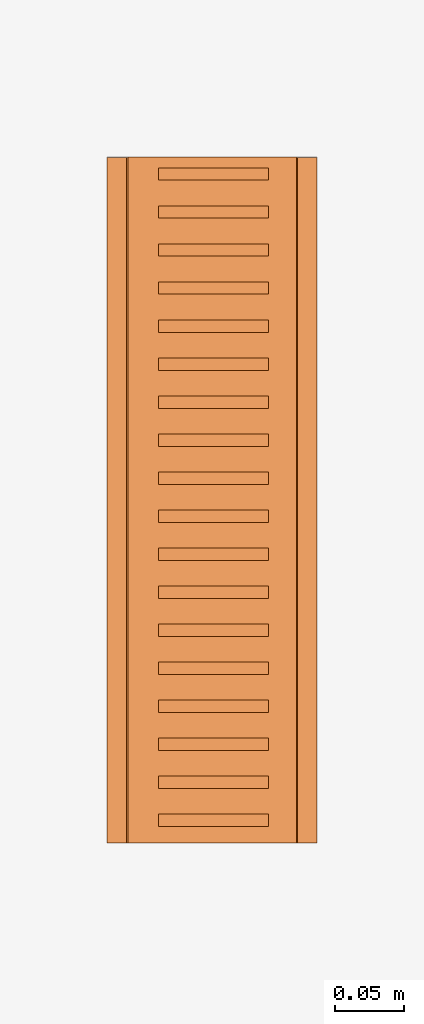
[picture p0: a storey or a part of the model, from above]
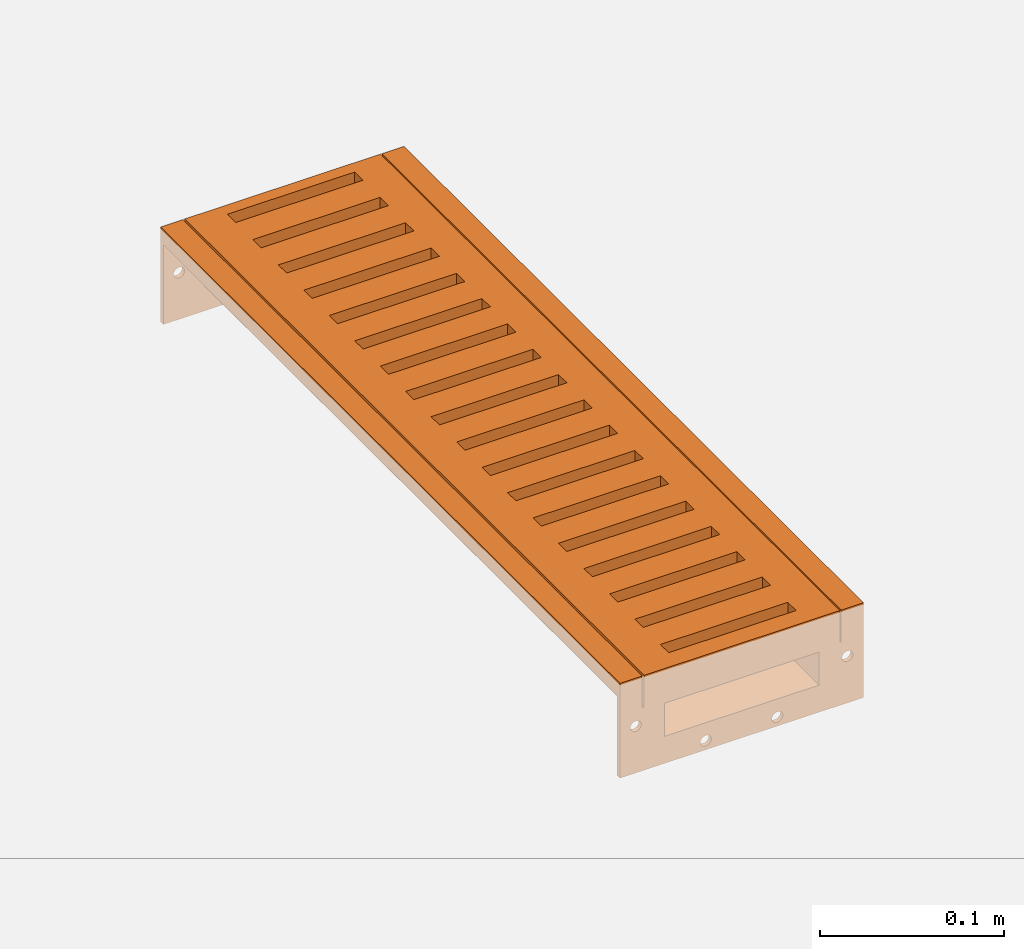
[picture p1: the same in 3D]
Properties of the parts of a building model (IFC2X3)

# File
Description: ViewDefinition [CoordinationView]
File name: 105254 - Level Invert Channel-500mm LG.ifc
Time: 2014-03-20T14:44:23
Written by: Autodesk Revit 2013
Made in: 20120221_2030(x64)

# IfcProject, Project Number
LongName: Project Name; Phase: Project Status

# IfcSite, Default
RefLatitude: 42, 21, 30, 344238; RefLongitude: -71, -3, -35, -194702; RefElevation: 0 mm

# IfcBuilding
Pset_BuildingCommon - NumberOfStoreys: 1
Other - Project Status: Project Status; Project Name: Project Name; Client Name: Owner; Project Number: Project Number; Project Address: ## Street City, State Zip; Project Issue Date: Issue Date

# IfcBuildingStorey, Level 1
LongName: Level 1; Elevation: 0 mm
Constraints - Elevation Base: 0; Elevation: 0 mm
Graphics - Line Pattern: Center; Color: 0; Line Weight: 1; Symbol: M_Level Head - Circle: M_Level Head - Circle; Symbol at End 1 Default: no; Symbol at End 2 Default: yes
Identity Data - Structural: no; Building Story: yes; Name: Level 1
Dimensions - Computation Height: 0 mm

# IfcBuildingElementProxy: 105254 - Level Invert Channel-500mm LG, ACO BD Deckline 125 Straight Channel:105254 - Level Invert Channel-500mm LG:105254 - Level Invert Channel-500mm LG:225886
In: Level 1
Material: Steel, Galvanized
Construction - 10735 - Composite Grating (White) - 500mm Long: no; 105508 - C250 Perforated Grating - 500mm Long: no; 105251 - Endplate - Invert 1: no; 105525 - C250 Slotted Grating - 1000mm Long: no; 105522 - A15 Slotted Grating - 500mm Long: no; 105524 - C250 Slotted Grating - 500mm Long: no; 105251 - Endplate - Invert 2: no; 15704 - Composite Grating (Black) - 500mm Long: no; 105509 - C250 Perforated Grating - 1000mm Long: no; 105523 - A15 Slotted Grating - 1000mm Long: no; Non Standard Channel: no; Standard Channel: yes; Grating: yes
Phasing - Phase Created: New Construction
Dimensions - Custom Channel: 494 mm; Custom Void: 2500 mm; Length: 500 mm; Void Length: -500 mm; EndCap Distance: 500 mm; Volume: 1450672 mm3; Channel Len: 494 mm
Constraints - Level: Level: Level 1; Moves With Nearby Elements: no
Pset_BuildingElementProxyCommon - Reference: 105254 - Level Invert Channel-500mm LG
Identity Data - Fax: +44 (0)1462 851490; E-mail Technical: abdtechnical@aco.co.uk; Watermark2: This file is water marked and users are prohibited to reproduce, adapt, distribute this information; Watermark1: This file is the property of ACO Technologies PLC; Telephone: +44 (0)1462 816666; Watermarked With: BIM Manager Premium Suite; Address: ACO Business Centre, Caxton Road, Bedford, MK41 0LF; Manufacturer: ACO Building Drainage; E-mail Sales: abdcommercial@aco.co.uk; Watermarked By: www.aco.co.uk; Website: www.acobd.com
General - Maintenance guidelines: X:\Electronic Literature\Building Drainage Literature\Deckline\Deckline 125.PDF; Weight (Kg): 2.3; Installation guidelines: X:\Electronic Literature\Building Drainage Literature\Deckline\Deckline 125.PDF; Dimensions (LxWxH): 500 x 153 x 63; Channel Recycled Material Content: 25 - 30 %; Seal Recyclable: Fully recyclable; Product Type: shallow invert surface water drainage system; Seal Recycled Material Content: 0%; Channel Recyclable: Fully recyclable; Load Class: A15 - C250; Seal Colour: Black; Product Range: ACO Deckline 125; Channel Material: Hot Dipped Galvanised Steel; Product Description: ACO Deckline Level Invert Channel (500 Long); Seal Material: Neoprene; Product Standard: BS EN 1433:2002 CE marked; Channel Colour: Galvanised; Product Code: 105254; Price: POA - contact ACO; NBS Specification: NBS Section Q10 Kerbs/edgings/channels/paving accessories, Clause 180 Drainage Channel Systems
Model Properties - Grating Product Code 105509: Load Class C250 - Perforated Galvanised Steel - 500mm long - 2.3kg; Grating Product Code 105522: Load Class A15 - Slotted Galvanised Steel - 1000mm long - 2.0kg; Grating Product Code 105523: Load Class A15 - Slotted Galvanised Steel - 500mm long - 1.0kg; Grating Product Code 105524: Load Class C250 - Slotted Galvanised Steel - 1000mm long - 4.7kg; Grating Product Code 15704: Load Class C250 - Composite Black - 500mm long - 1.2kg; Grating Product Code 105525: Load Class C250 - Slotted Galvanised Steel - 500mm long - 2.3kg; Grating Product Code 105508: Load Class C250 - Perforated Galvanised Steel - 1000mm long - 4.8kg; Grating Product Code 10735: Load Class C250 - Composite White - 500mm long - 1.2kg

# IfcOpeningElement: Recess
In: Level 1
Constraints - Height Offset From Level: 0 mm; Level: Level: Level 1; Room Bounding: yes; Related to Mass: no
Phasing - Phase Created: New Construction
Dimensions - Volume: 6395181268 mm3; Area: 16000000 mm2; Perimeter: 16000 mm; Thickness: 400 mm
Structural - Structural: no; Enable Analytical Model: no
Construction - Function: 0; Default Thickness: 400 mm
Analytical Properties - Thermal mass: 604440; Thermal Resistance (R): 0.382409; Heat Transfer Coefficient (U): 2.615; Absorptance: 0.1; Roughness: 1
Graphics - Coarse Scale Fill Color: 0
Materials and Finishes - Structural Material: Concrete, Broom Finish

# IfcSlab: Floor:Generic Floor - 400mm, Floor:Generic Floor - 400mm:193825
In: Level 1
PredefinedType: FLOOR; Material: Concrete, Broom Finish 400 mm
Constraints - Height Offset From Level: 0 mm; Level: Level: Level 1; Room Bounding: yes; Related to Mass: no
Phasing - Phase Created: New Construction
Dimensions - Volume: 6395181268 mm3; Area: 16000000 mm2; Perimeter: 16000 mm; Thickness: 400 mm
Structural - Structural: no; Enable Analytical Model: no
Pset_SlabCommon - Reference: Generic Floor - 400mm; IsExternal: no; LoadBearing: yes
Construction - Function: 0; Default Thickness: 400 mm
Analytical Properties - Thermal mass: 604440; Thermal Resistance (R): 0.382409; Heat Transfer Coefficient (U): 2.615; Absorptance: 0.1; Roughness: 1
Graphics - Coarse Scale Fill Color: 0
Materials and Finishes - Structural Material: Concrete, Broom Finish
